VERSION 5.7 ;
  NOWIREEXTENSIONATPIN ON ;
  DIVIDERCHAR "/" ;
  BUSBITCHARS "[]" ;
UNITS
  DATABASE MICRONS 100 ;
END UNITS

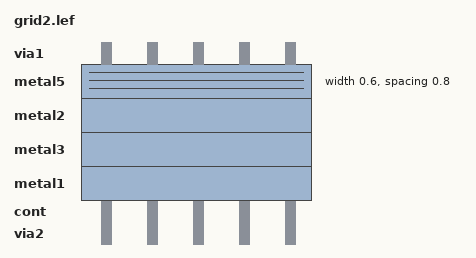
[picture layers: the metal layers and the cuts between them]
LAYER via2
  TYPE CUT ;
END via2

LAYER NWELL
  TYPE MASTERSLICE ;
END NWELL

LAYER cont
  TYPE CUT ;
END cont

LAYER metal1
  TYPE ROUTING ;
END metal1

LAYER metal3
  TYPE ROUTING ;
END metal3

LAYER metal2
  TYPE ROUTING ;
END metal2

LAYER metal5
  TYPE ROUTING ;
  WIDTH 0.600000 ;
  SPACING 0.800000 ;
  DIRECTION HORIZONTAL ;
END metal5

LAYER POLY
  TYPE MASTERSLICE ;
END POLY

LAYER via1
  TYPE CUT ;
END via1

MACRO top
  CLASS BLOCK ;
  FOREIGN top ;
  ORIGIN 0.00 0.00 ;
  SIZE 1.00 BY 1.00 ;
  OBS
      LAYER metal1 ;
        RECT 0.00 0.00 1.00 1.00 ;
  END
END top
END LIBRARY

